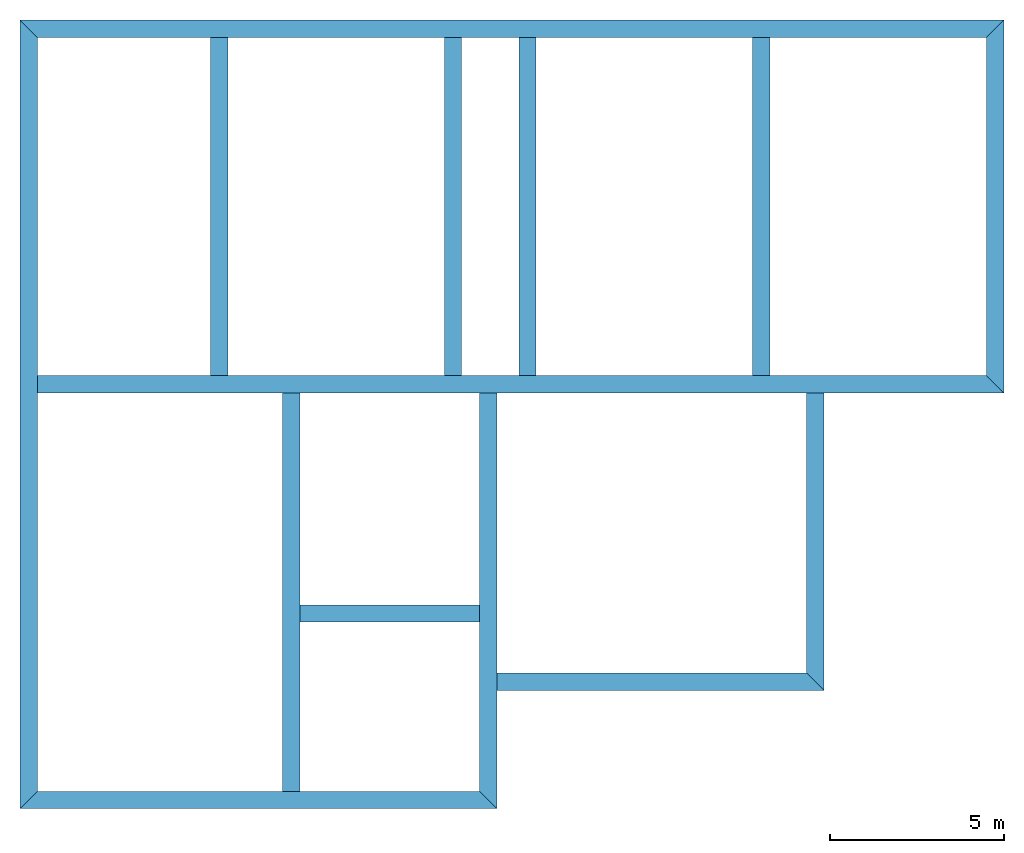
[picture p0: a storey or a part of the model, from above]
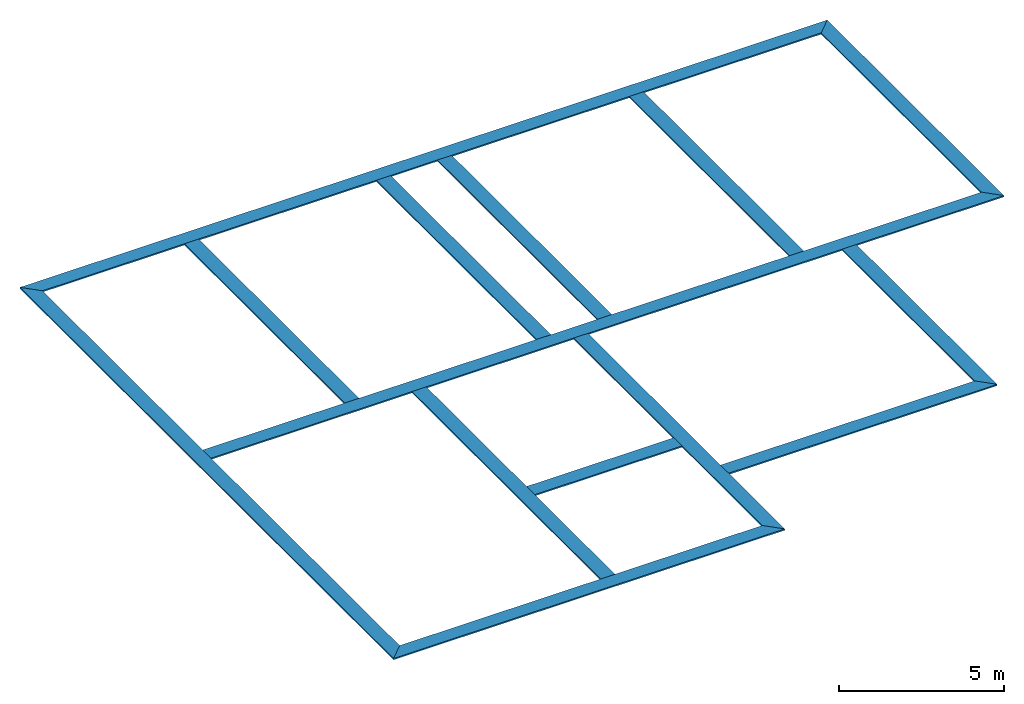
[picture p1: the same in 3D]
Properties of the parts of a building model (IFC2X3)

# File
Description: ViewDefinition [CoordinationView_V2.0], Option [Elements to export: Visible elements (on all stories)], Option [Partial Structure Display: Entire Model], Option [IFC Domain: All], Option [Structural Function: All Elements], Option [Convert Grid elements: On], Option [Convert IFC Annotations and Archicad 2D elements: Off], Option [Convert 2D symbols of Doors and Windows: Off], Option [Export geometries that Participates in Collision Detection only: Off], Option [Split complex elements: Off], Option [Material Preservation: Explode where necessary], Option [Elements in Solid Element Operations: Extruded/revolved], Option [Elements with junctions: Extruded/revolved without junctions], Option [IFC Model position: Survey Point and Project Origin], Option [Curtain Wall export mode: Container Element], Option [Railing export mode: Single Element], Option [Stair export mode: Container Element], Option [Properties To Export: All properties], Option [Space containment: Off], Option [Geometry to type objects: Off], Option [Element Properties: Off], Option [Building Material Properties: Off], Option [Element Parameters: Off], Option [Component Parameters: Off], Option [IFC Base Quantities: Off], Option [Door Window Parameters: Off], Option [IFC Space boundaries: Off], Option [Archicad Zone Categories as IFC Space classification data: Off], Option [Element Classifications: On]
File name: /Users/julienlaragne/Desktop/Maquette Bim jan 2023.ifc
Time: 2023-01-25T17:13:34
Author: Architect
Organization: Building Designer Office
Written by: The EXPRESS Data Manager Version 5.02.0100.09 : 18 Aug 2016
Made in: IFC file generated by Graphisoft Archicad 26.0.0 FRA FULL Macintosh version (IFC add-on version: 3001 FRA FULL).
Authorization: The authorising person

# IfcSite, Site
RefLatitude: 48, 51, 12, 248500; RefLongitude: 2, 20, 55, 625630; RefElevation: 400 m

# IfcBuildingStorey (5)
In: Bâtiment
Name | Elevation (m)
Fonds de fouilles / béton de propreté | -0.78
Fondations | -0.73
Soubassements | -0.53
Rez-de-chaussée | 0
Toitures | 3

# IfcBeam: Couvertine mur 390 x 590 (2)
In: Toitures
Type - PredefinedType: BEAM
Classification: Poutre (Classification ARCHICAD)
Pset_BeamCommon - Slope: 0 deg; IsExternal: no; Reference: Couvertine mur 390 x 590
AC_Pset_RenovationAndPhasing - Renovation Status: Existing
Name | Span (m)
POUTRE-001 | 12.1298
POUTRE-001 | 8.77987

# IfcBeam: Couvertine mur bardage 555 x 590 (3)
In: Toitures
Type - PredefinedType: BEAM
Classification: Poutre (Classification ARCHICAD)
Pset_BeamCommon - Slope: 0 deg; IsExternal: no; Reference: Couvertine mur bardage 555 x 590
AC_Pset_RenovationAndPhasing - Renovation Status: Existing
Name | Span (m)
POUTRE-001 | 9.955
POUTRE-002 | 9.263
POUTRE-003 | 1.79

# IfcBeam: couvertine mur iso 505 x 590 (7)
In: Toitures
Type - PredefinedType: BEAM
Classification: Poutre (Classification ARCHICAD)
Pset_BeamCommon - Slope: 0 deg; IsExternal: no; Reference: couvertine mur iso 505 x 590
AC_Pset_RenovationAndPhasing - Renovation Status: Existing
Name | Span (m)
POUTRE-001 | 6.91
POUTRE-002 | 10.837
POUTRE-003 | 5.12
POUTRE-001 | 8.045
POUTRE-002 | 12.1298
POUTRE-001 | 3.41996
POUTRE-002 | 5.795

# IfcBuildingElementPart (177)
Name | In | Material
14 x Finition int - Enduit plâtre | Rez-de-chaussée | Finition int - Enduit plâtre
8 x Béton armé (Coulé) | Rez-de-chaussée | Béton armé (Coulé)
2 x Isolation - Fibres de bois | Rez-de-chaussée | Isolation - Fibres de bois
2 x Finition int - Enduit minéral | Rez-de-chaussée | Finition int - Enduit minéral
46 x Finition int - Plaque de plâtre | Rez-de-chaussée | Finition int - Plaque de plâtre
15 x Isolation - Laine de verre | Rez-de-chaussée | Isolation - Laine de verre
3 x Cloison - Carreaux de plâtre | Rez-de-chaussée | Cloison - Carreaux de plâtre
4 x Acier inoxydable | Toitures | Acier inoxydable
34 x Isolation - Polyuréthane (extérieur) | Toitures | Isolation - Polyuréthane (extérieur)
17 x Etanchéité | Toitures | Etanchéité
Bois OSB | Toitures | Bois OSB
Panneaux sandwich | Toitures | Panneaux sandwich
6 x Plaque fibre-gypse | Toitures | Plaque fibre-gypse
18 x Aluminium | Toitures | Aluminium
6 x Vide faux plafond | Toitures | Vide faux plafond

# IfcBuildingElementProxy: Texte 3D 26, MOBILIER-0018
In: Rez-de-chaussée
Type - ElementType: CONSTRUCTION ELEMENT; PredefinedType: USERDEFINED
Classification: Elément de construction (Classification ARCHICAD)
AC_Pset_RenovationAndPhasing - Renovation Status: Existing

# IfcColumn: GEN - Structurel 300 x 300, POTEAU-001
In: Rez-de-chaussée
Type - PredefinedType: COLUMN
Classification: Poteau (Classification ARCHICAD); Material: GEN - Structurel
Pset_ColumnCommon - Slope: 90 deg; IsExternal: yes; Reference: GEN - Structurel 300 x 300
AC_Pset_RenovationAndPhasing - Renovation Status: Existing

# IfcColumn: GEN - Structurel 50 x 50 (318)
In: Rez-de-chaussée
Type - PredefinedType: COLUMN
Classification: Poteau (Classification ARCHICAD); Material: GEN - Structurel
Pset_ColumnCommon - Slope: 90 deg; IsExternal: yes; Reference: GEN - Structurel 50 x 50
AC_Pset_RenovationAndPhasing - Renovation Status: Existing

# IfcDoor: Porte 26 (9)
In: Rez-de-chaussée
Type - OperationType: SINGLE_SWING_LEFT; ParameterTakesPrecedence: no; Sizeable: no
OverallHeight: 2.1 m; Classification: Porte (Classification ARCHICAD)
Pset_DoorCommon - ThermalTransmittance: 0; IsExternal: no
AC_Pset_RenovationAndPhasing - Renovation Status: Existing
Name | OverallWidth (m) | IsCombustible
8 x PORTE-PP90 A2 - PF1/2H | 1 | yes
PORTE-002 | 0.58

# IfcDoor: Porte 26 (4)
In: Rez-de-chaussée
Type - OperationType: SINGLE_SWING_RIGHT; ParameterTakesPrecedence: no; Sizeable: no
OverallHeight: 2.1 m; OverallWidth: 1 m; Classification: Porte (Classification ARCHICAD)
Pset_DoorCommon - ThermalTransmittance: 0; IsExternal: no
AC_Pset_RenovationAndPhasing - Renovation Status: Existing
Name | IsCombustible
3 x PORTE-PP90 A2 - PF1/2H | yes
PORTE-002

# IfcDoor: Porte double 26 (7)
In: Rez-de-chaussée
Type - OperationType: DOUBLE_DOOR_SINGLE_SWING; ParameterTakesPrecedence: no; Sizeable: no
Classification: Porte (Classification ARCHICAD)
Pset_DoorCommon - ThermalTransmittance: 0; IsExternal: no
AC_Pset_RenovationAndPhasing - Renovation Status: Existing
Name | OverallHeight (m) | OverallWidth (m) | IsCombustible
2 x PORTE-PP90 A2 - PF1/2H | 2.25 | 1.93987 | yes | Pset_DoorCommon - GlazingAreaFraction: 3.16803
PP 90+40 - A2 - PF 1/2H | 2.1 | 1.4 | yes
PP 90x2 - A2 - PF 1/2H | 2.1 | 1.9 | yes
3 x PORTE-002 | 2.1 | 1.6

# IfcDoor: Porte double avec tierce vitrée 26, PORTE-PP90 A2 - PF1/2H
In: Rez-de-chaussée
Type - OperationType: USERDEFINED; ParameterTakesPrecedence: no; Sizeable: no
OverallHeight: 2.25 m; OverallWidth: 3.76 m; Classification: Porte (Classification ARCHICAD)
Pset_DoorCommon - ThermalTransmittance: 0; GlazingAreaFraction: 6.50151; IsExternal: no
Pset_FireRatingProperties - IsCombustible: yes
AC_Pset_RenovationAndPhasing - Renovation Status: Existing

# IfcRoof (5)
In: Toitures
Classification: Toiture (Classification ARCHICAD)
AC_Pset_RenovationAndPhasing - Renovation Status: Existing
Pset_RoofCommon - IsExternal: yes
Name
4 x TOIT-001
TOIT-002

# IfcSlab: Béton armé (Coulé) 130, Sol moquette tufté en dalle
In: Rez-de-chaussée
Type - PredefinedType: FLOOR
Classification: Dalle de sol (Classification ARCHICAD); Material: Béton armé (Coulé) 0.13 m
Pset_SlabCommon - AcousticRating: 26 dB; Combustible: yes; IsExternal: no; LoadBearing: no
Pset_FireRatingProperties - IsCombustible: yes
Pset_ManufacturerOccurrence - SerialNumber: Sol moquette tufté dalle - TESSERA MIX / FORBO. Réaction au feu: Bfl-s1 / classement revètement : U3P3E1C0 / pose collée sur ragréage type P3
AC_Pset_RenovationAndPhasing - Renovation Status: Existing

# IfcSlab: Béton armé (Coulé) 150, DALLE-001
In: Rez-de-chaussée
Type - PredefinedType: FLOOR
Classification: Dalle de sol (Classification ARCHICAD); Material: Béton armé (Coulé) 0.15 m
AC_Pset_RenovationAndPhasing - Renovation Status: Existing
Pset_SlabCommon - IsExternal: no

# IfcSlab: Dalle basse sur terre plein sans rvt 520, DALLE-001
In: Rez-de-chaussée
Type - PredefinedType: FLOOR
Classification: Dalle de sol (Classification ARCHICAD); Material: Chape ciment 0.07 m, Béton armé (Coulé) 0.13 m, Isolation - Polystyrène extrudé 0.09 m, Sable 0.05 m, Gravier 0.18 m
AC_Pset_RenovationAndPhasing - Renovation Status: Existing
Pset_SlabCommon - IsExternal: no

# IfcSlab: Finition sol - Parquet 10, Sol souple pose collée
In: Rez-de-chaussée
Type - PredefinedType: FLOOR
Classification: Dalle de sol (Classification ARCHICAD); Material: Finition sol - Parquet 0.01 m
Pset_ManufacturerOccurrence - SerialNumber: Sol souple pose collée ALLURA 0,7 WOOD / FORBO. Epaisseur 2,5mm - Réaction au feu: Bfl-s1 / classement revètement : U4P3E2C2 / Classement COV: A+ / pose collée sur ragréage type P3
Pset_SlabCommon - Combustible: yes; IsExternal: no; LoadBearing: no
Pset_FireRatingProperties - IsCombustible: yes
AC_Pset_RenovationAndPhasing - Renovation Status: Existing

# IfcSlab: Linoleum 10 (2)
In: Rez-de-chaussée
Type - PredefinedType: FLOOR
Classification: Dalle de sol (Classification ARCHICAD); Material: Linoleum 0.01 m
Pset_SlabCommon - Combustible: yes; IsExternal: no; LoadBearing: no
Pset_FireRatingProperties - IsCombustible: yes
Pset_ManufacturerOccurrence - SerialNumber: Sol souple pose collée - SARLON TRAFIC MODUL'UP / FORBO. Epaisseur 4mm - classement revètement : U4P4E3C3 / pose collée sur ragréage type P3
AC_Pset_RenovationAndPhasing - Renovation Status: Existing

# IfcSlab: Moquette 10, Sol moquette tufté en dalle
In: Rez-de-chaussée
Type - PredefinedType: FLOOR
Classification: Dalle de sol (Classification ARCHICAD); Material: Moquette 0.01 m
Pset_SlabCommon - AcousticRating: 26 dB; Combustible: yes; IsExternal: no; LoadBearing: no
Pset_FireRatingProperties - IsCombustible: yes
Pset_ManufacturerOccurrence - SerialNumber: Sol moquette tufté dalle - TESSERA MIX / FORBO. Réaction au feu: Bfl-s1 / classement revètement : U3P3E1C0 / pose collée sur ragréage type P3
AC_Pset_RenovationAndPhasing - Renovation Status: Existing

# IfcSlab: Plafond Classe 800, Faux plafonds suspendus
In: Toitures
Type - PredefinedType: FLOOR
Classification: Dalle de sol (Classification ARCHICAD); Material: Isolation - Laine de verre 0.14 m, Isolation - Laine de verre 0.14 m, Vide faux plafond 0.45 m, Aluminium 0.06 m, Plaque fibre-gypse 0.01 m
Pset_SlabCommon - AcousticRating: aw = 0,70; IsExternal: no
Pset_ManufacturerOccurrence - SerialNumber: Plafonds suspendus GYPTONE ACTIV'AIR LINE 4A / PLACO - 600x600 - Blanc RAL 9010 - Classement feu A2-s1,D0
AC_Pset_RenovationAndPhasing - Renovation Status: Existing

# IfcSlab: Plafond Dgt Dortoir 1200 (4)
In: Toitures
Type - PredefinedType: FLOOR
Classification: Dalle de sol (Classification ARCHICAD); Material: Isolation - Laine de verre 0.14 m, Isolation - Laine de verre 0.14 m, Vide faux plafond 0.85 m, Aluminium 0.06 m, Plaque fibre-gypse 0.01 m
Pset_SlabCommon - IsExternal: no
AC_Pset_RenovationAndPhasing - Renovation Status: Existing
Name | AcousticRating | SerialNumber
2 x Plafond suspendu 600x600 | aw = 0,60 | Faux plafonds en dalles de 600x600 type DANOLINE ISO-TONE HYGIENNE / KNAUF - Décor QUADRILL - teinte RAL 9003 - Suspension BELGRAVIA ossature T15 - Classement feu A2-s1, d0
2 x Faux plafonds suspendus | aw = 0,70 | Plafonds suspendus GYPTONE ACTIV'AIR LINE 4A / PLACO - 600x600 - Blanc RAL 9010 - Classement feu A2-s1,D0

# IfcSlab: Plafond dalles minérale 2570 (5)
In: Toitures
Type - PredefinedType: FLOOR
Classification: Dalle de sol (Classification ARCHICAD)
AC_Pset_RenovationAndPhasing - Renovation Status: Existing
Pset_SlabCommon - IsExternal: no
Name | AcousticRating | SerialNumber
DALLE-004
Plafond acoustique suspendu | aw = 0,70 | Plafond suspendu SIERRA / ARMSTRONG - 600x600 - Blanc standard - Classement feu A2-s1, d0
2 x Faux plafonds suspendus | aw = 0,70 | Plafonds suspendus GYPTONE ACTIV'AIR LINE 4A / PLACO - 600x600 - Blanc RAL 9010 - Classement feu A2-s1,D0
DALLE-005

# IfcSlab: Plafond plaque de platre 1018, DALLE-008
In: Toitures
Type - PredefinedType: FLOOR
Classification: Dalle de sol (Classification ARCHICAD)
AC_Pset_RenovationAndPhasing - Renovation Status: Existing
Pset_SlabCommon - IsExternal: no

# IfcWall: Carreaux de platre 80 (3)
In: Rez-de-chaussée
Classification: Mur (Classification ARCHICAD)
Pset_ConcreteElementGeneral - ConstructionType: Murs porteurs extérieurs
AC_Pset_RenovationAndPhasing - Renovation Status: Existing
Pset_WallCommon - IsExternal: yes

# IfcWall: Cloison 100/48 100 (5)
In: Rez-de-chaussée
Classification: Mur (Classification ARCHICAD)
Pset_ConcreteElementGeneral - ConstructionType: Murs porteurs extérieurs
AC_Pset_RenovationAndPhasing - Renovation Status: Existing
Pset_WallCommon - IsExternal: yes
Name
2 x MUR_EXT-009
2 x MUR_EXT-008
MUR_EXT-006

# IfcWall: Cloison 50 50 (4)
In: Rez-de-chaussée
Classification: Mur (Classification ARCHICAD)
Pset_ConcreteElementGeneral - ConstructionType: Murs porteurs extérieurs
AC_Pset_RenovationAndPhasing - Renovation Status: Existing
Pset_WallCommon - IsExternal: yes
Name
3 x MUR_EXT-006
MUR_EXT-007

# IfcWall: Cloison 72/48 70 (6)
In: Rez-de-chaussée
Classification: Mur (Classification ARCHICAD)
Pset_ConcreteElementGeneral - ConstructionType: Murs porteurs extérieurs
AC_Pset_RenovationAndPhasing - Renovation Status: Existing
Pset_WallCommon - IsExternal: yes

# IfcWall: Couvertine mur bardage 555 x 590, MUR_EXT-013
In: Toitures
Classification: Mur (Classification ARCHICAD)
Pset_ConcreteElementGeneral - ConstructionType: Murs porteurs extérieurs
AC_Pset_RenovationAndPhasing - Renovation Status: Existing
Pset_WallCommon - IsExternal: yes

# IfcWall: Finition int - Enduit minéral 173, MUR_EXT-007
In: Toitures
Classification: Mur (Classification ARCHICAD); Material: Finition int - Enduit minéral
Pset_ConcreteElementGeneral - ConstructionType: Murs porteurs extérieurs
AC_Pset_RenovationAndPhasing - Renovation Status: Existing
Pset_WallCommon - IsExternal: yes

# IfcWall: Finition int - Enduit minéral 55 (2)
In: Toitures
Classification: Mur (Classification ARCHICAD); Material: Finition int - Enduit minéral
Pset_ConcreteElementGeneral - ConstructionType: Murs porteurs extérieurs
AC_Pset_RenovationAndPhasing - Renovation Status: Existing
Pset_WallCommon - IsExternal: yes

# IfcWall: Mur 20cm + enduit 2cm 240 (5)
In: Rez-de-chaussée
Classification: Mur (Classification ARCHICAD)
Pset_ConcreteElementGeneral - ConstructionType: Murs porteurs extérieurs
AC_Pset_RenovationAndPhasing - Renovation Status: Existing
Pset_WallCommon - IsExternal: yes
Name
4 x MUR_EXT-007
MUR_EXT-005

# IfcWall: Mur 20cm + enduit 2cm copie 260, MUR_EXT-007
In: Rez-de-chaussée
Classification: Mur (Classification ARCHICAD)
Pset_ConcreteElementGeneral - ConstructionType: Murs porteurs extérieurs
AC_Pset_RenovationAndPhasing - Renovation Status: Existing
Pset_WallCommon - IsExternal: yes

# IfcWall: Mur 20cm + iso 18 + enduit 410 (2)
In: Rez-de-chaussée
Classification: Mur (Classification ARCHICAD)
Pset_ConcreteElementGeneral - ConstructionType: Murs porteurs extérieurs
Pset_WallCommon - ThermalTransmittance: 0; IsExternal: yes
Pset_ManufacturerOccurrence - SerialNumber: Mur de façade panneaux isolant STO THERMWOOD M039 sur support béton, finition enduit STO LEVELL UNI 7mm
AC_Pset_RenovationAndPhasing - Renovation Status: Existing

# IfcWallStandardCase: Béton armé (Coulé) 500 (14)
In: Fondations
Classification: Mur (Classification ARCHICAD); Material: Béton armé (Coulé) 0.5 m
Pset_ConcreteElementGeneral - ConstructionType: Murs porteurs extérieurs
AC_Pset_RenovationAndPhasing - Renovation Status: Existing
Pset_WallCommon - IsExternal: yes
Name
MUR_EXT-001
MUR_EXT-002
MUR_EXT-003
MUR_EXT-004
MUR_EXT-005
MUR_EXT-006
7 x MUR_EXT-007
MUR_EXT-008

# IfcWallStandardCase: Béton maigre 500 (14)
In: Fonds de fouilles / béton de propreté
Classification: Mur (Classification ARCHICAD); Material: Béton maigre 0.5 m
Pset_ConcreteElementGeneral - ConstructionType: Murs porteurs extérieurs
AC_Pset_RenovationAndPhasing - Renovation Status: Existing
Pset_WallCommon - IsExternal: yes
Name
MUR_EXT-001
MUR_EXT-002
MUR_EXT-003
MUR_EXT-004
MUR_EXT-005
MUR_EXT-006
7 x MUR_EXT-007
MUR_EXT-008

# IfcWallStandardCase: Cloison 100/48 100, MUR_EXT-009
In: Rez-de-chaussée
Classification: Mur (Classification ARCHICAD); Material: Finition int - Plaque de plâtre 0.013 m, Finition int - Plaque de plâtre 0.013 m, Isolation - Laine de verre 0.048 m, Finition int - Plaque de plâtre 0.013 m, Finition int - Plaque de plâtre 0.013 m
Pset_ConcreteElementGeneral - ConstructionType: Murs porteurs extérieurs
AC_Pset_RenovationAndPhasing - Renovation Status: Existing
Pset_WallCommon - IsExternal: yes

# IfcWallStandardCase: Cloison 50 50 (7)
Classification: Mur (Classification ARCHICAD); Material: Finition int - Plaque de plâtre 0.013 m, Isolation - Laine de verre 0.024 m, Finition int - Plaque de plâtre 0.013 m
Pset_ConcreteElementGeneral - ConstructionType: Murs porteurs extérieurs
AC_Pset_RenovationAndPhasing - Renovation Status: Existing
Pset_WallCommon - IsExternal: yes
Name | In
5 x MUR_EXT-006 | Rez-de-chaussée
2 x MUR_EXT-006 | Toitures

# IfcWallStandardCase: Cloison 72/48 70 (19)
In: Rez-de-chaussée
Classification: Mur (Classification ARCHICAD); Material: Finition int - Plaque de plâtre 0.013 m, Isolation - Laine de verre 0.044 m, Finition int - Plaque de plâtre 0.013 m
Pset_ConcreteElementGeneral - ConstructionType: Murs porteurs extérieurs
AC_Pset_RenovationAndPhasing - Renovation Status: Existing
Pset_WallCommon - IsExternal: yes
Name
17 x MUR_EXT-006
MUR_EXT-007
MUR_EXT-008

# IfcWallStandardCase: Cloison SAD 160 159, Cloison SAD 160
In: Rez-de-chaussée
Classification: Mur (Classification ARCHICAD); Material: Finition int - Plaque de plâtre 0.013 m, Finition int - Plaque de plâtre 0.0125 m, Isolation - Laine de verre 0.048 m, Armature de cloison 0.012 m, Isolation - Laine de verre 0.048 m, Finition int - Plaque de plâtre 0.0125 m, Finition int - Plaque de plâtre 0.0125 m
Pset_ConcreteElementGeneral - ConstructionType: Murs porteurs extérieurs
Pset_WallCommon - AcousticRating: 64 dB; FireRating: 60; ThermalTransmittance: 0.54; IsExternal: yes
Pset_FireRatingProperties - FireResistanceRating: 60
Pset_ManufacturerOccurrence - SerialNumber: Cloison SAD 160 - Epaisseur totale 160mm - ossature 2x48mm - isolant 45mm - parement double peau - Hauteur max 3,40m
AC_Pset_RenovationAndPhasing - Renovation Status: Existing

# IfcWallStandardCase: Mur 20cm + enduit 2cm 240 (4)
In: Rez-de-chaussée
Classification: Mur (Classification ARCHICAD); Material: Finition int - Enduit plâtre 0.02 m, Béton armé (Coulé) 0.2 m, Finition int - Enduit plâtre 0.02 m
Pset_ConcreteElementGeneral - ConstructionType: Murs porteurs extérieurs
AC_Pset_RenovationAndPhasing - Renovation Status: Existing
Pset_WallCommon - IsExternal: yes
Name
2 x MUR_EXT-006
MUR_EXT-007
MUR_EXT-005

# IfcWallStandardCase: Mur 20cm + iso 18 + enduit 410 (9)
In: Rez-de-chaussée
Classification: Mur (Classification ARCHICAD); Material: Finition int - Enduit minéral 0.01 m, Isolation - Fibres de bois 0.18 m, Béton armé (Coulé) 0.2 m, Finition int - Enduit plâtre 0.02 m
Pset_ConcreteElementGeneral - ConstructionType: Murs porteurs extérieurs
Pset_WallCommon - ThermalTransmittance: 0; IsExternal: yes
Pset_ManufacturerOccurrence - SerialNumber: Mur de façade panneaux isolant STO THERMWOOD M039 sur support béton, finition enduit STO LEVELL UNI 7mm
AC_Pset_RenovationAndPhasing - Renovation Status: Existing

# IfcWallStandardCase: Mur soubassement béton 20cm 200 (14)
In: Soubassements
Classification: Mur (Classification ARCHICAD); Material: Béton armé (Coulé) 0.2 m
Pset_ConcreteElementGeneral - ConstructionType: Murs porteurs extérieurs
AC_Pset_RenovationAndPhasing - Renovation Status: Existing
Pset_WallCommon - IsExternal: yes
Name
MUR_EXT-001
MUR_EXT-002
2 x MUR_EXT-005
MUR_EXT-004
MUR_EXT-006
7 x MUR_EXT-007
MUR_EXT-008

# IfcWindow: Fenêtre 26 (4)
In: Rez-de-chaussée
Type - OperationType: SINGLE_PANEL; ParameterTakesPrecedence: no; Sizeable: no
Classification: Fenêtre (Classification ARCHICAD)
Pset_WindowCommon - ThermalTransmittance: 0; IsExternal: yes
AC_Pset_RenovationAndPhasing - Renovation Status: Existing
Name | OverallHeight (m) | OverallWidth (m) | GlazingAreaFraction
FENETRE-005 | 2.25 | 1.18 | 1.919
2 x FENETRE-005 | 1.65 | 0.74 | 0.7242
FENETRE-005 | 2.25 | 2.22 | 4.2622

# IfcWindow: Fenêtre châssis double 26, FENETRE-005
In: Rez-de-chaussée
Type - OperationType: DOUBLE_PANEL_VERTICAL; ParameterTakesPrecedence: no; Sizeable: no
OverallHeight: 2.25 m; OverallWidth: 1.54 m; Classification: Fenêtre (Classification ARCHICAD)
Pset_WindowCommon - ThermalTransmittance: 0; IsExternal: yes
AC_Pset_RenovationAndPhasing - Renovation Status: Existing

# IfcWindow: Fenêtre horizontale à châssis multiples 26, Portes placard couliisantes 1x2panneaux
In: Rez-de-chaussée
Type - OperationType: DOUBLE_PANEL_VERTICAL; ParameterTakesPrecedence: no; Sizeable: no
OverallHeight: 2.13 m; OverallWidth: 1.67 m; Classification: Fenêtre (Classification ARCHICAD)
Pset_WindowCommon - ThermalTransmittance: 0; IsExternal: yes
AC_Pset_RenovationAndPhasing - Renovation Status: Existing

# IfcWindow: Fenêtre horizontale à châssis multiples 26, FENETRE-005
In: Rez-de-chaussée
Type - OperationType: TRIPLE_PANEL_VERTICAL; ParameterTakesPrecedence: no; Sizeable: no
OverallHeight: 2.25 m; OverallWidth: 2.68 m; Classification: Fenêtre (Classification ARCHICAD)
Pset_WindowCommon - ThermalTransmittance: 0; GlazingAreaFraction: 4.3026; IsExternal: yes
AC_Pset_RenovationAndPhasing - Renovation Status: Existing

# IfcWindow: Fenêtre horizontale à châssis multiples 26 (9)
In: Rez-de-chaussée
Type - OperationType: USERDEFINED; ParameterTakesPrecedence: no; Sizeable: no
Classification: Fenêtre (Classification ARCHICAD)
Pset_WindowCommon - ThermalTransmittance: 0; IsExternal: yes
AC_Pset_RenovationAndPhasing - Renovation Status: Existing
Name | OverallHeight (m) | OverallWidth (m) | GlazingAreaFraction
3 x FENETRE-005 | 2.25 | 5.76 | 9.9182
FENETRE-005 | 2.25 | 2.75 | 4.1208
FENETRE-005 | 2.25 | 3.42 | 5.4742
2 x Portes placard couliisantes 4x2panneaux | 2.13 | 6.66
Portes placard couliisantes 5x2panneaux | 2.13 | 8.33
Portes placard couliisantes 3x2panneaux | 2.13 | 7.83
